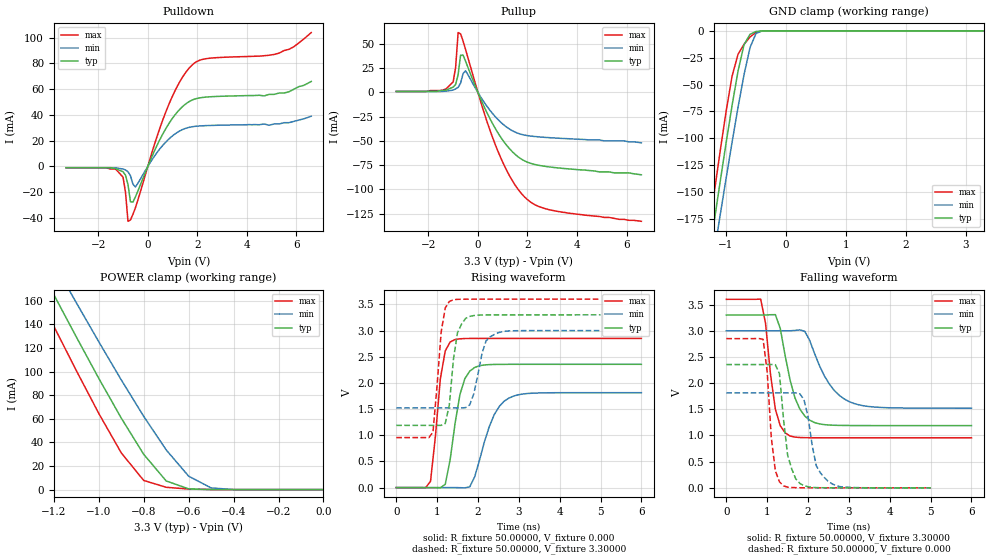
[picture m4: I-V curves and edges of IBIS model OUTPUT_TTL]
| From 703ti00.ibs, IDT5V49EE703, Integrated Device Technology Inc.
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|   Model OUTPUT_TTL
[Model]   OUTPUT_TTL
Model_type   3-state
Polarity   Non-Inverting
Enable   Active-High
Vmeas =  1.65000V
C_comp   7.85000pF   7.85000pF   7.85000pF
[Temperature Range]   25.00000   100.00000   -40.00000
[Voltage Range]   3.30000V   3.00000V   3.60000V
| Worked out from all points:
|   slope of the pulldown table from 0 to 0.495 V, typ, clamps not added: 23.4 ohm
|   slope of the pullup table from 0 to 0.495 V, typ, clamps not added: 18 ohm
|   GND clamp passes 1 mA (typ) near -0.51 V on its own axis
|   POWER clamp passes 1 mA (typ) near -0.61 V on its own axis
|   rising waveform, R_fixture 50.00000, V_fixture 0.000: 20-80 % time 297ps typ, 465ps min, 223ps max; typ from 0 V to 2.35 V
|   rising waveform, R_fixture 50.00000, V_fixture 3.30000: 20-80 % time 180ps typ, 252ps min, 174ps max; typ from 1.19 V to 3.3 V
|   falling waveform, R_fixture 50.00000, V_fixture 3.30000: 20-80 % time 382ps typ, 605ps min, 238ps max; typ from 3.3 V to 1.19 V
|   falling waveform, R_fixture 50.00000, V_fixture 0.000: 20-80 % time 224ps typ, 274ps min, 172ps max; typ from 2.35 V to 0 V
[Pulldown]
| voltage   I(typ)   I(min)   I(max)
-3.3V     -1mA       -1mA       -1mA
-1.3V     -1.8mA     -1.1mA     -2mA
-1V       -4.1mA     -2mA       -8.3mA
-900mV    -6.8mA     -2.7mA     -20.1mA
-800mV    -14.1mA    -4.1mA     -42.61mA
-700mV    -27.47mA   -7.2mA     -41.53mA
-600mV    -27.69mA   -13.78mA   -37.22mA
700mV     28.47mA    18.42mA    40.99mA
1.7V      50.72mA    30.51mA    77.06mA
2.3V      53.79mA    31.67mA    83.54mA
5.3V      57mA       33mA       88mA
6.6V      66mA       39mA       104mA
[Pullup]
| voltage   I(typ)   I(min)   I(max)
-3.3V     1mA        1mA        1mA
-1.3V     2.3mA      1.3mA      3.4mA
-1V       5.5mA      2.4mA      10.9mA
-900mV    8.3mA      3.7mA      25.9mA
-800mV    18.2mA     5.2mA      61.79mA
-700mV    38.4mA     9.6mA      60.42mA
-600mV    38.5mA     19.47mA    52.99mA
-500mV    32.24mA    22.32mA    44.42mA
700mV     -37.14mA   -25mA      -53.77mA
1.9V      -70.87mA   -44.11mA   -108.3mA
2.9V      -76.93mA   -46.71mA   -121.2mA
6.6V      -85mA      -52mA      -133mA
[GND_clamp]
| voltage   I(typ)   I(min)   I(max)
-3.3V     -992.9mA   -970.1mA   -1.017A
-1.3V     -215.6mA   -242.3mA   -191.1mA
-1.2V     -178mA     -207mA     -151.4mA
-1.1V     -140.9mA   -172mA     -112.5mA
-1V       -104.5mA   -137.5mA   -75.29mA
-900mV    -69.52mA   -103.7mA   -42.26mA
-800mV    -37.35mA   -71.1mA    -21.75mA
-700mV    -12.91mA   -40.75mA   -12.54mA
-600mV    -3.185mA   -15.58mA   -5.724mA
-500mV    -635.8uA   -2.421mA   -1.438mA
-400mV    -69.98uA   -165.2uA   -148uA
3.3V      688.8pA    4.084uA    187.4pA
[POWER_clamp]
| voltage   I(typ)   I(min)   I(max)
-3.3V     952mA      926.9mA    968.4mA
-1.3V     201.5mA    226mA      176.7mA
-1.2V     165.2mA    192mA      138.4mA
-1.1V     129.4mA    158.4mA    100.9mA
-1V       94.29mA    125.3mA    64.57mA
-900mV    60.64mA    93mA       31.15mA
-800mV    29.89mA    62.06mA    7.756mA
-700mV    7.344mA    33.66mA    1.97mA
-600mV    611uA      11.37mA    451.7uA
-500mV    56.05uA    1.412mA    58.07uA
-400mV    5.393uA    79.29uA    5.064uA
0V        688.9pA    3.732nA    251.1pA
[Ramp]
| variable   typ   min   max
dV/dt_r   1.41300/0.28312n   1.08780/0.45593n   1.71000/0.19614n
dV/dt_f   1.26660/0.37242n   0.88740/0.60123n   1.58658/0.23503n
R_load = 50.00000
[Rising Waveform]
R_fixture = 50.00000
V_fixture = 0.000
V_fixture_min = 0.000
V_fixture_max = 0.000
| time   V(typ)   V(min)   V(max)
0s        0V         0V         0V
840ps     389nV      0V         120mV
1.08ns    -3.91mV    0V         2.077V
1.2ns     61.81mV    -195.7nV   2.61V
1.32ns    532.5mV    4.131uV    2.782V
1.56ns    1.78V      -1.431mV   2.842V
1.92ns    2.295V     205mV      2.849V
2.4ns     2.353V     1.395V     2.849V
2.76ns    2.355V     1.71V      2.85V
6ns       2.355V     1.813V     2.85V
[Rising Waveform]
R_fixture = 50.00000
V_fixture = 3.30000
V_fixture_min = 3.00000
V_fixture_max = 3.60000
| time   V(typ)   V(min)   V(max)
0s        1.189V     1.521V     955.6mV
900ps     1.189V     1.521V     1.061V
1.1ns     1.189V     1.521V     2.969V
1.3ns     1.578V     1.521V     3.555V
1.5ns     2.959V     1.521V     3.596V
1.7ns     3.233V     1.528V     3.599V
1.9ns     3.287V     1.794V     3.599V
2.1ns     3.297V     2.564V     3.599V
2.3ns     3.299V     2.88V      3.599V
5ns       3.3V       2.999V     3.6V
[Falling Waveform]
R_fixture = 50.00000
V_fixture = 3.30000
V_fixture_min = 3.00000
V_fixture_max = 3.60000
| time   V(typ)   V(min)   V(max)
0s        3.3V       3V         3.6V
840ps     3.3V       3V         3.604V
960ps     3.3V       3V         3.139V
1.2ns     3.308V     3V         1.501V
1.56ns    2.058V     2.999V     989.3mV
1.8ns     1.504V     3.017V     961.6mV
2.04ns    1.292V     2.815V     957.4mV
2.52ns    1.2V       1.984V     956.2mV
3ns       1.191V     1.649V     955.9mV
6ns       1.189V     1.521V     955.7mV
[Falling Waveform]
R_fixture = 50.00000
V_fixture = 0.000
V_fixture_min = 0.000
V_fixture_max = 0.000
| time   V(typ)   V(min)   V(max)
0s        2.355V     1.813V     2.85V
900ps     2.355V     1.813V     2.837V
1.2ns     2.351V     1.813V     323.9mV
1.3ns     2.183V     1.813V     116.1mV
1.4ns     1.309V     1.813V     37.5mV
1.7ns     170.6mV    1.813V     3.489mV
1.9ns     43.15mV    1.687V     1.161mV
2.2ns     4.678mV    425.4mV    477.7uV
2.5ns     1.552mV    119.2mV    343.1uV
5ns       169.3uV    369.6uV    88.74uV
